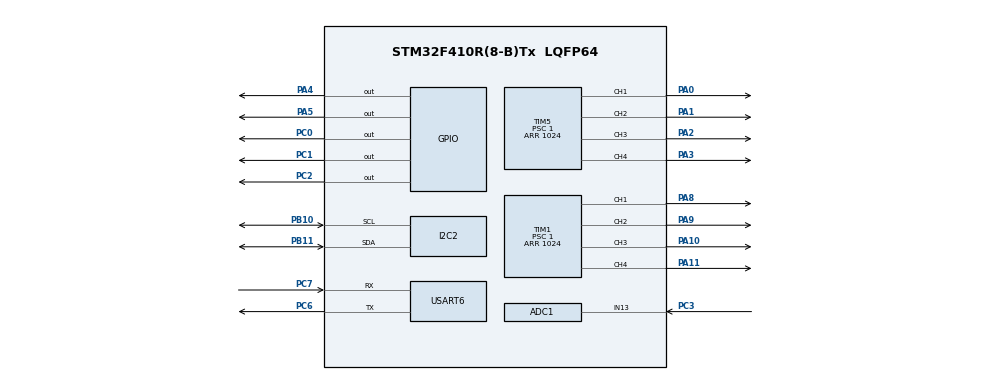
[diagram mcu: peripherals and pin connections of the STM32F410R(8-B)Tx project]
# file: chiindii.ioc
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ADC1.Channel-0\#ChannelRegularConversion=ADC_CHANNEL_13
ADC1.NbrOfConversionFlag=1
ADC1.Rank-0\#ChannelRegularConversion=1
ADC1.SamplingTime-0\#ChannelRegularConversion=ADC_SAMPLETIME_3CYCLES
ADC1.master=1
Mcu.Family=STM32F4
Mcu.Name=STM32F410R(8-B)Tx
Mcu.Package=LQFP64
NVIC.PriorityGroup=NVIC_PRIORITYGROUP_4
PA0-WKUP.Signal=S_TIM5_CH1
PA1.Signal=S_TIM5_CH2
PA10.Signal=S_TIM1_CH3
PA11.Signal=S_TIM1_CH4
PA13.Mode=Trace-Asynchronous_SW
PA13.Signal=SYS_JTMS-SWDIO
PA14.Mode=Trace-Asynchronous_SW
PA14.Signal=SYS_JTCK-SWCLK
PA2.Signal=S_TIM5_CH3
PA3.Signal=S_TIM5_CH4
PA4.Signal=GPIO_Output
PA5.Signal=GPIO_Output
PA8.Signal=S_TIM1_CH1
PA9.Signal=S_TIM1_CH2
PB10.Mode=I2C
PB10.Signal=I2C2_SCL
PB11.Mode=I2C
PB11.Signal=I2C2_SDA
PB3.Mode=Trace-Asynchronous_SW
PB3.Signal=SYS_JTDO-SWO
PC0.Signal=GPIO_Output
PC1.Signal=GPIO_Output
PC2.Signal=GPIO_Output
PC3.Signal=ADCx_IN13
PC6.Mode=Asynchronous
PC6.Signal=USART6_TX
PC7.Mode=Asynchronous
PC7.Signal=USART6_RX
ProjectManager.HeapSize=0x400
ProjectManager.StackSize=0x200
ProjectManager.TargetToolchain=TrueSTUDIO
RCC.48MHZClocksFreq_Value=50000000
RCC.AHBFreq_Value=100000000
RCC.APB1CLKDivider=RCC_HCLK_DIV4
RCC.APB1Freq_Value=25000000
RCC.APB1TimFreq_Value=50000000
RCC.APB2CLKDivider=RCC_HCLK_DIV4
RCC.APB2Freq_Value=25000000
RCC.APB2TimFreq_Value=50000000
RCC.CortexFreq_Value=100000000
RCC.HCLKFreq_Value=100000000
RCC.HSE_VALUE=25000000
RCC.HSI_VALUE=16000000
RCC.LSE_VALUE=32768
RCC.PLLM=8
RCC.PLLN=100
RCC.SYSCLKFreq_VALUE=100000000
RCC.SYSCLKSource=RCC_SYSCLKSOURCE_PLLCLK
RCC.VCOOutputFreq_Value=200000000
SH.ADCx_IN13.0=ADC1_IN13,IN13
SH.S_TIM1_CH1.0=TIM1_CH1,PWM Generation1 CH1
SH.S_TIM1_CH2.0=TIM1_CH2,PWM Generation2 CH2
SH.S_TIM1_CH3.0=TIM1_CH3,PWM Generation3 CH3
SH.S_TIM1_CH4.0=TIM1_CH4,PWM Generation4 CH4
SH.S_TIM5_CH1.0=TIM5_CH1,PWM Generation1 CH1
SH.S_TIM5_CH2.0=TIM5_CH2,PWM Generation2 CH2
SH.S_TIM5_CH3.0=TIM5_CH3,PWM Generation3 CH3
SH.S_TIM5_CH4.0=TIM5_CH4,PWM Generation4 CH4
TIM1.Channel-PWM\ Generation2\ CH2=TIM_CHANNEL_2
TIM1.Channel-PWM\ Generation3\ CH3=TIM_CHANNEL_3
TIM1.Channel-PWM\ Generation4\ CH4=TIM_CHANNEL_4
TIM1.ClockDivision=TIM_CLOCKDIVISION_DIV4
TIM1.Period=1024
TIM1.Prescaler=1
TIM5.Channel-PWM\ Generation2\ CH2=TIM_CHANNEL_2
TIM5.Channel-PWM\ Generation3\ CH3=TIM_CHANNEL_3
TIM5.Channel-PWM\ Generation4\ CH4=TIM_CHANNEL_4
TIM5.Period=1024
TIM5.Prescaler=1
VP_TIM1_VS_ClockSourceINT.Mode=Internal
VP_TIM5_VS_ClockSourceINT.Mode=Internal
board=chiindii

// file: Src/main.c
/**
  ******************************************************************************
  * File Name          : main.c
  * Description        : Main program body
  ******************************************************************************
  *
  * COPYRIGHT(c) 2016 STMicroelectronics
  *
  * Redistribution and use in source and binary forms, with or without modification,
  * are permitted provided that the following conditions are met:
  *   1. Redistributions of source code must retain the above copyright notice,
  *      this list of conditions and the following disclaimer.
  *   2. Redistributions in binary form must reproduce the above copyright notice,
  *      this list of conditions and the following disclaimer in the documentation
  *      and/or other materials provided with the distribution.
  *   3. Neither the name of STMicroelectronics nor the names of its contributors
  *      may be used to endorse or promote products derived from this software
  *      without specific prior written permission.
  *
  * THIS SOFTWARE IS PROVIDED BY THE COPYRIGHT HOLDERS AND CONTRIBUTORS "AS IS"
  * AND ANY EXPRESS OR IMPLIED WARRANTIES, INCLUDING, BUT NOT LIMITED TO, THE
  * IMPLIED WARRANTIES OF MERCHANTABILITY AND FITNESS FOR A PARTICULAR PURPOSE ARE
  * DISCLAIMED. IN NO EVENT SHALL THE COPYRIGHT HOLDER OR CONTRIBUTORS BE LIABLE
  * FOR ANY DIRECT, INDIRECT, INCIDENTAL, SPECIAL, EXEMPLARY, OR CONSEQUENTIAL
  * DAMAGES (INCLUDING, BUT NOT LIMITED TO, PROCUREMENT OF SUBSTITUTE GOODS OR
  * SERVICES; LOSS OF USE, DATA, OR PROFITS; OR BUSINESS INTERRUPTION) HOWEVER
  * CAUSED AND ON ANY THEORY OF LIABILITY, WHETHER IN CONTRACT, STRICT LIABILITY,
  * OR TORT (INCLUDING NEGLIGENCE OR OTHERWISE) ARISING IN ANY WAY OUT OF THE USE
  * OF THIS SOFTWARE, EVEN IF ADVISED OF THE POSSIBILITY OF SUCH DAMAGE.
  *
  ******************************************************************************
  */
#include "stm32f4xx_hal.h"

ADC_HandleTypeDef hadc1;

I2C_HandleTypeDef hi2c2;

TIM_HandleTypeDef htim1;
TIM_HandleTypeDef htim5;

UART_HandleTypeDef huart6;

/* USER CODE BEGIN PV */
/* Private variables ---------------------------------------------------------*/

/* USER CODE END PV */

void SystemClock_Config(void);
static void MX_GPIO_Init(void);
static void MX_ADC1_Init(void);
static void MX_I2C2_Init(void);
static void MX_TIM1_Init(void);
static void MX_TIM5_Init(void);
static void MX_USART6_UART_Init(void);

void HAL_TIM_MspPostInit(TIM_HandleTypeDef *htim);

/* USER CODE BEGIN PFP */
/* Private function prototypes -----------------------------------------------*/

/* USER CODE END PFP */

int main(void)
{

  /* MCU Configuration----------------------------------------------------------*/

  /* Reset of all peripherals, Initializes the Flash interface and the Systick. */
  HAL_Init();

  /* Configure the system clock */
  SystemClock_Config();

  /* Initialize all configured peripherals */
  MX_GPIO_Init();
  MX_ADC1_Init();
  MX_I2C2_Init();
  MX_TIM1_Init();
  MX_TIM5_Init();
  MX_USART6_UART_Init();

  /* Infinite loop */
  while (1)
  {

  }

}

/** System Clock Configuration
*/
void SystemClock_Config(void)
{

  RCC_OscInitTypeDef RCC_OscInitStruct;
  RCC_ClkInitTypeDef RCC_ClkInitStruct;

  __PWR_CLK_ENABLE();

  __HAL_PWR_VOLTAGESCALING_CONFIG(PWR_REGULATOR_VOLTAGE_SCALE1);

  RCC_OscInitStruct.OscillatorType = RCC_OSCILLATORTYPE_HSI;
  RCC_OscInitStruct.HSIState = RCC_HSI_ON;
  RCC_OscInitStruct.HSICalibrationValue = 16;
  RCC_OscInitStruct.PLL.PLLState = RCC_PLL_NONE;
  HAL_RCC_OscConfig(&RCC_OscInitStruct);

  RCC_ClkInitStruct.ClockType = RCC_CLOCKTYPE_HCLK|RCC_CLOCKTYPE_SYSCLK
                              |RCC_CLOCKTYPE_PCLK1|RCC_CLOCKTYPE_PCLK2;
  RCC_ClkInitStruct.SYSCLKSource = RCC_SYSCLKSOURCE_HSI;
  RCC_ClkInitStruct.AHBCLKDivider = RCC_SYSCLK_DIV1;
  RCC_ClkInitStruct.APB1CLKDivider = RCC_HCLK_DIV1;
  RCC_ClkInitStruct.APB2CLKDivider = RCC_HCLK_DIV1;
  HAL_RCC_ClockConfig(&RCC_ClkInitStruct, FLASH_LATENCY_0);

  HAL_SYSTICK_Config(HAL_RCC_GetHCLKFreq()/1000);

  HAL_SYSTICK_CLKSourceConfig(SYSTICK_CLKSOURCE_HCLK);

  /* SysTick_IRQn interrupt configuration */
  HAL_NVIC_SetPriority(SysTick_IRQn, 0, 0);
}

/* ADC1 init function */
void MX_ADC1_Init(void)
{

  ADC_ChannelConfTypeDef sConfig;

    /**Configure the global features of the ADC (Clock, Resolution, Data Alignment and number of conversion)
    */
  hadc1.Instance = ADC1;
  hadc1.Init.ClockPrescaler = ADC_CLOCKPRESCALER_PCLK_DIV2;
  hadc1.Init.Resolution = ADC_RESOLUTION12b;
  hadc1.Init.ScanConvMode = DISABLE;
  hadc1.Init.ContinuousConvMode = DISABLE;
  hadc1.Init.DiscontinuousConvMode = DISABLE;
  hadc1.Init.ExternalTrigConvEdge = ADC_EXTERNALTRIGCONVEDGE_NONE;
  hadc1.Init.DataAlign = ADC_DATAALIGN_RIGHT;
  hadc1.Init.NbrOfConversion = 1;
  hadc1.Init.DMAContinuousRequests = DISABLE;
  hadc1.Init.EOCSelection = EOC_SINGLE_CONV;
  HAL_ADC_Init(&hadc1);

    /**Configure for the selected ADC regular channel its corresponding rank in the sequencer and its sample time.
    */
  sConfig.Channel = ADC_CHANNEL_13;
  sConfig.Rank = 1;
  sConfig.SamplingTime = ADC_SAMPLETIME_3CYCLES;
  HAL_ADC_ConfigChannel(&hadc1, &sConfig);

}

/* I2C2 init function */
void MX_I2C2_Init(void)
{

  hi2c2.Instance = I2C2;
  hi2c2.Init.ClockSpeed = 100000;
  hi2c2.Init.DutyCycle = I2C_DUTYCYCLE_2;
  hi2c2.Init.OwnAddress1 = 0;
  hi2c2.Init.AddressingMode = I2C_ADDRESSINGMODE_7BIT;
  hi2c2.Init.DualAddressMode = I2C_DUALADDRESS_DISABLED;
  hi2c2.Init.OwnAddress2 = 0;
  hi2c2.Init.GeneralCallMode = I2C_GENERALCALL_DISABLED;
  hi2c2.Init.NoStretchMode = I2C_NOSTRETCH_DISABLED;
  HAL_I2C_Init(&hi2c2);

}

/* TIM1 init function */
void MX_TIM1_Init(void)
{

  TIM_ClockConfigTypeDef sClockSourceConfig;
  TIM_MasterConfigTypeDef sMasterConfig;
  TIM_BreakDeadTimeConfigTypeDef sBreakDeadTimeConfig;
  TIM_OC_InitTypeDef sConfigOC;

  htim1.Instance = TIM1;
  htim1.Init.Prescaler = 0;
  htim1.Init.CounterMode = TIM_COUNTERMODE_UP;
  htim1.Init.Period = 0;
  htim1.Init.ClockDivision = TIM_CLOCKDIVISION_DIV1;
  htim1.Init.RepetitionCounter = 0;
  HAL_TIM_Base_Init(&htim1);

  sClockSourceConfig.ClockSource = TIM_CLOCKSOURCE_INTERNAL;
  HAL_TIM_ConfigClockSource(&htim1, &sClockSourceConfig);

  HAL_TIM_PWM_Init(&htim1);

  sMasterConfig.MasterOutputTrigger = TIM_TRGO_RESET;
  sMasterConfig.MasterSlaveMode = TIM_MASTERSLAVEMODE_DISABLE;
  HAL_TIMEx_MasterConfigSynchronization(&htim1, &sMasterConfig);

  sBreakDeadTimeConfig.OffStateRunMode = TIM_OSSR_DISABLE;
  sBreakDeadTimeConfig.OffStateIDLEMode = TIM_OSSI_DISABLE;
  sBreakDeadTimeConfig.LockLevel = TIM_LOCKLEVEL_OFF;
  sBreakDeadTimeConfig.DeadTime = 0;
  sBreakDeadTimeConfig.BreakState = TIM_BREAK_DISABLE;
  sBreakDeadTimeConfig.BreakPolarity = TIM_BREAKPOLARITY_HIGH;
  sBreakDeadTimeConfig.AutomaticOutput = TIM_AUTOMATICOUTPUT_DISABLE;
  HAL_TIMEx_ConfigBreakDeadTime(&htim1, &sBreakDeadTimeConfig);

  sConfigOC.OCMode = TIM_OCMODE_PWM1;
  sConfigOC.Pulse = 0;
  sConfigOC.OCPolarity = TIM_OCPOLARITY_HIGH;
  sConfigOC.OCNPolarity = TIM_OCNPOLARITY_HIGH;
  sConfigOC.OCFastMode = TIM_OCFAST_DISABLE;
  sConfigOC.OCIdleState = TIM_OCIDLESTATE_RESET;
  sConfigOC.OCNIdleState = TIM_OCNIDLESTATE_RESET;
  HAL_TIM_PWM_ConfigChannel(&htim1, &sConfigOC, TIM_CHANNEL_1);

  HAL_TIM_PWM_ConfigChannel(&htim1, &sConfigOC, TIM_CHANNEL_2);

  HAL_TIM_PWM_ConfigChannel(&htim1, &sConfigOC, TIM_CHANNEL_3);

  HAL_TIM_PWM_ConfigChannel(&htim1, &sConfigOC, TIM_CHANNEL_4);

  HAL_TIM_MspPostInit(&htim1);

}

/* TIM5 init function */
void MX_TIM5_Init(void)
{

  TIM_ClockConfigTypeDef sClockSourceConfig;
  TIM_MasterConfigTypeDef sMasterConfig;
  TIM_OC_InitTypeDef sConfigOC;

  htim5.Instance = TIM5;
  htim5.Init.Prescaler = 0;
  htim5.Init.CounterMode = TIM_COUNTERMODE_UP;
  htim5.Init.Period = 0;
  htim5.Init.ClockDivision = TIM_CLOCKDIVISION_DIV1;
  HAL_TIM_Base_Init(&htim5);

  sClockSourceConfig.ClockSource = TIM_CLOCKSOURCE_INTERNAL;
  HAL_TIM_ConfigClockSource(&htim5, &sClockSourceConfig);

  HAL_TIM_PWM_Init(&htim5);

  sMasterConfig.MasterOutputTrigger = TIM_TRGO_RESET;
  sMasterConfig.MasterSlaveMode = TIM_MASTERSLAVEMODE_DISABLE;
  HAL_TIMEx_MasterConfigSynchronization(&htim5, &sMasterConfig);

  sConfigOC.OCMode = TIM_OCMODE_PWM1;
  sConfigOC.Pulse = 0;
  sConfigOC.OCPolarity = TIM_OCPOLARITY_HIGH;
  sConfigOC.OCFastMode = TIM_OCFAST_DISABLE;
  HAL_TIM_PWM_ConfigChannel(&htim5, &sConfigOC, TIM_CHANNEL_1);

  HAL_TIM_PWM_ConfigChannel(&htim5, &sConfigOC, TIM_CHANNEL_2);

  HAL_TIM_PWM_ConfigChannel(&htim5, &sConfigOC, TIM_CHANNEL_3);

  HAL_TIM_PWM_ConfigChannel(&htim5, &sConfigOC, TIM_CHANNEL_4);

  HAL_TIM_MspPostInit(&htim5);

}

/* USART6 init function */
void MX_USART6_UART_Init(void)
{

  huart6.Instance = USART6;
  huart6.Init.BaudRate = 115200;
  huart6.Init.WordLength = UART_WORDLENGTH_8B;
  huart6.Init.StopBits = UART_STOPBITS_1;
  huart6.Init.Parity = UART_PARITY_NONE;
  huart6.Init.Mode = UART_MODE_TX_RX;
  huart6.Init.HwFlowCtl = UART_HWCONTROL_NONE;
  huart6.Init.OverSampling = UART_OVERSAMPLING_16;
  HAL_UART_Init(&huart6);

}

/** Configure pins as
        * Analog
        * Input
        * Output
        * EVENT_OUT
        * EXTI
*/
void MX_GPIO_Init(void)
{

  GPIO_InitTypeDef GPIO_InitStruct;

  /* GPIO Ports Clock Enable */
  __GPIOC_CLK_ENABLE();
  __GPIOA_CLK_ENABLE();
  __GPIOB_CLK_ENABLE();

  /*Configure GPIO pin Output Level */
  HAL_GPIO_WritePin(GPIOC, GPIO_PIN_0|GPIO_PIN_1|GPIO_PIN_2, GPIO_PIN_RESET);

  /*Configure GPIO pin Output Level */
  HAL_GPIO_WritePin(GPIOA, GPIO_PIN_4|GPIO_PIN_5, GPIO_PIN_RESET);

  /*Configure GPIO pins : PC0 PC1 PC2 */
  GPIO_InitStruct.Pin = GPIO_PIN_0|GPIO_PIN_1|GPIO_PIN_2;
  GPIO_InitStruct.Mode = GPIO_MODE_OUTPUT_PP;
  GPIO_InitStruct.Pull = GPIO_NOPULL;
  GPIO_InitStruct.Speed = GPIO_SPEED_LOW;
  HAL_GPIO_Init(GPIOC, &GPIO_InitStruct);

  /*Configure GPIO pins : PA4 PA5 */
  GPIO_InitStruct.Pin = GPIO_PIN_4|GPIO_PIN_5;
  GPIO_InitStruct.Mode = GPIO_MODE_OUTPUT_PP;
  GPIO_InitStruct.Pull = GPIO_NOPULL;
  GPIO_InitStruct.Speed = GPIO_SPEED_LOW;
  HAL_GPIO_Init(GPIOA, &GPIO_InitStruct);

}

/************************ (C) COPYRIGHT STMicroelectronics *****END OF FILE****/
